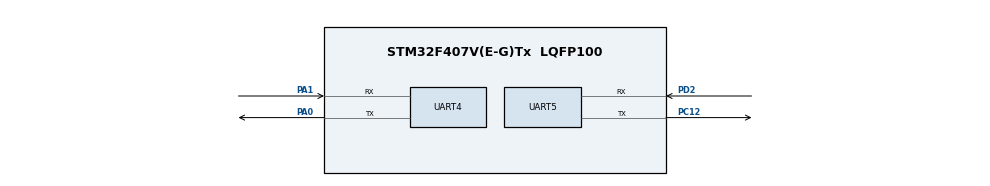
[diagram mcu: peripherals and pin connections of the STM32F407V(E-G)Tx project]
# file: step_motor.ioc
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Mcu.Family=STM32F4
Mcu.Name=STM32F407V(E-G)Tx
Mcu.Package=LQFP100
NVIC.PriorityGroup=NVIC_PRIORITYGROUP_4
NVIC.UART4_IRQn=true\:0\:0\:false\:false\:true\:true\:true\:true
NVIC.UART5_IRQn=true\:1\:0\:true\:false\:true\:true\:true\:true
PA0-WKUP.Mode=Asynchronous
PA0-WKUP.Signal=UART4_TX
PA1.Mode=Asynchronous
PA1.Signal=UART4_RX
PA13.Mode=Serial_Wire
PA13.Signal=SYS_JTMS-SWDIO
PA14.Mode=Serial_Wire
PA14.Signal=SYS_JTCK-SWCLK
PC12.Mode=Asynchronous
PC12.Signal=UART5_TX
PD2.Mode=Asynchronous
PD2.Signal=UART5_RX
PH0-OSC_IN.Mode=HSE-External-Oscillator
PH0-OSC_IN.Signal=RCC_OSC_IN
PH1-OSC_OUT.Mode=HSE-External-Oscillator
PH1-OSC_OUT.Signal=RCC_OSC_OUT
ProjectManager.HeapSize=0x200
ProjectManager.StackSize=0x400
ProjectManager.TargetToolchain=STM32CubeIDE
RCC.48MHZClocksFreq_Value=84000000
RCC.AHBFreq_Value=168000000
RCC.APB1CLKDivider=RCC_HCLK_DIV4
RCC.APB1Freq_Value=42000000
RCC.APB1TimFreq_Value=84000000
RCC.APB2CLKDivider=RCC_HCLK_DIV2
RCC.APB2Freq_Value=84000000
RCC.APB2TimFreq_Value=168000000
RCC.CortexFreq_Value=168000000
RCC.HCLKFreq_Value=168000000
RCC.HSE_VALUE=8000000
RCC.HSI_VALUE=16000000
RCC.LSE_VALUE=32768
RCC.PLLM=4
RCC.PLLN=168
RCC.PLLSourceVirtual=RCC_PLLSOURCE_HSE
RCC.SYSCLKFreq_VALUE=168000000
RCC.SYSCLKSource=RCC_SYSCLKSOURCE_PLLCLK
RCC.VCOOutputFreq_Value=336000000
UART4.VirtualMode=Asynchronous
UART5.VirtualMode=Asynchronous
board=custom

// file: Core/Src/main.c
/* USER CODE BEGIN Header */
/**
  ******************************************************************************
  * @file           : main.c
  * @brief          : Main program body
  ******************************************************************************
  * @attention
  *
  * Copyright (c) 2025 STMicroelectronics.
  * All rights reserved.
  *
  * This software is licensed under terms that can be found in the LICENSE file
  * in the root directory of this software component.
  * If no LICENSE file comes with this software, it is provided AS-IS.
  *
  ******************************************************************************
  */
/* USER CODE END Header */
#include "main.h"
#include "usart.h"
#include "gpio.h"

/* USER CODE BEGIN Includes */
#include "retarget.h"
#include "step_motor.h"
/* USER CODE END Includes */

void SystemClock_Config(void);

int main(void)
{

  /* MCU Configuration--------------------------------------------------------*/

  /* Reset of all peripherals, Initializes the Flash interface and the Systick. */
  HAL_Init();

  /* Configure the system clock */
  SystemClock_Config();

  /* Initialize all configured peripherals */
  MX_GPIO_Init();
  MX_UART4_Init();
  MX_UART5_Init();
  /* USER CODE BEGIN 2 */
  motor1.huart=&huart4;
  motor1.id=0x01;
  motor2.huart=&huart4;
  motor2.id=0x02;

    RetargetInit(&huart5);
    printf("hello\r\n");

    Step_Motor_Enable(&motor1);
	HAL_Delay(100);
	Step_Motor_Enable(&motor2);
    HAL_Delay(100);
//    Step_Motor_Vel_Control(&motor1,CCW,15,0x05,0x00);
//    HAL_Delay(100);
    Step_Motor_Pos_Contrpl(&motor1,CW,1500,10,720,RE_POS,SIN_START);
	HAL_Delay(100);
	Step_Motor_Pos_Contrpl(&motor2,CW,1500,10,720,RE_POS,SIN_START);

//    HAL_Delay(3000);
//    Step_Motor_Get_Cur_Pos(&motor1);
//    Step_Motor_Get_Cur_Vel(&motor1);
//    Step_Motor_Stop(&motor1);
//    Step_Motor_Disable(&motor1);
    HAL_Delay(100);
  /* USER CODE END 2 */

  /* Infinite loop */
  /* USER CODE BEGIN WHILE */
    while (1) {
//        Step_Motor_Get_Cur_Pos(&motor1);
//        Step_Motor_Vel_Control(&motor1,CCW,1500,0x05,0x00);
//        HAL_Delay(1000);
//        Step_Motor_Get_Cur_Vel(&motor1);
    /* USER CODE END WHILE */

    }
}

void SystemClock_Config(void)
{
  RCC_OscInitTypeDef RCC_OscInitStruct = {0};
  RCC_ClkInitTypeDef RCC_ClkInitStruct = {0};

  /** Configure the main internal regulator output voltage
  */
  __HAL_RCC_PWR_CLK_ENABLE();
  __HAL_PWR_VOLTAGESCALING_CONFIG(PWR_REGULATOR_VOLTAGE_SCALE1);

    // 先将时钟源选择为内部时钟
    RCC_ClkInitStruct.ClockType = RCC_CLOCKTYPE_SYSCLK;
    RCC_ClkInitStruct.SYSCLKSource = RCC_SYSCLKSOURCE_HSI;
    if (HAL_RCC_ClockConfig(&RCC_ClkInitStruct, FLASH_LATENCY_5) != HAL_OK)
    {
        Error_Handler();
    }
  /** Initializes the RCC Oscillators according to the specified parameters
  * in the RCC_OscInitTypeDef structure.
  */
  RCC_OscInitStruct.OscillatorType = RCC_OSCILLATORTYPE_HSE;
  RCC_OscInitStruct.HSEState = RCC_HSE_ON;
  RCC_OscInitStruct.PLL.PLLState = RCC_PLL_ON;
  RCC_OscInitStruct.PLL.PLLSource = RCC_PLLSOURCE_HSE;
  RCC_OscInitStruct.PLL.PLLM = 4;
  RCC_OscInitStruct.PLL.PLLN = 168;
  RCC_OscInitStruct.PLL.PLLP = RCC_PLLP_DIV2;
  RCC_OscInitStruct.PLL.PLLQ = 4;
  if (HAL_RCC_OscConfig(&RCC_OscInitStruct) != HAL_OK)
  {
    Error_Handler();
  }

  /** Initializes the CPU, AHB and APB buses clocks
  */
  RCC_ClkInitStruct.ClockType = RCC_CLOCKTYPE_HCLK|RCC_CLOCKTYPE_SYSCLK
                              |RCC_CLOCKTYPE_PCLK1|RCC_CLOCKTYPE_PCLK2;
  RCC_ClkInitStruct.SYSCLKSource = RCC_SYSCLKSOURCE_PLLCLK;
  RCC_ClkInitStruct.AHBCLKDivider = RCC_SYSCLK_DIV1;
  RCC_ClkInitStruct.APB1CLKDivider = RCC_HCLK_DIV4;
  RCC_ClkInitStruct.APB2CLKDivider = RCC_HCLK_DIV2;

  if (HAL_RCC_ClockConfig(&RCC_ClkInitStruct, FLASH_LATENCY_5) != HAL_OK)
  {
    Error_Handler();
  }

    // 禁用内部高速时钟
    RCC_OscInitStruct.OscillatorType = RCC_OSCILLATORTYPE_HSI;
    RCC_OscInitStruct.HSIState = RCC_HSI_OFF;
    RCC_OscInitStruct.PLL.PLLState = RCC_PLL_NONE;
    if(HAL_RCC_OscConfig(&RCC_OscInitStruct) != HAL_OK)
    {
        Error_Handler();
    }
}

void Error_Handler(void)
{
    __disable_irq();
    while (1) {
    }
}
